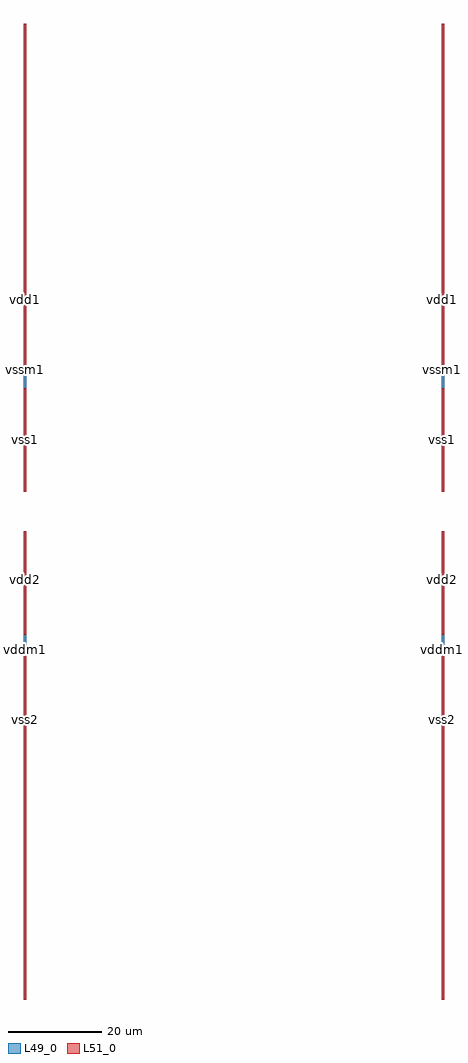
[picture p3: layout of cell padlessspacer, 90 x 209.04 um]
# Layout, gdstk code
import gdstk
lib = gdstk.Library(unit=1e-6, precision=1e-08)
def R(c, l, rs):  # rectangles x0, y0, x1, y1
    for r in rs: c.add(gdstk.rectangle(r[:2], r[2:], *l))
L49_0 = (49, 0)
L51_0 = (51, 0)

padlessspacer = lib.new_cell('padlessspacer')
R(padlessspacer, L49_0, [(0,0,0.48,100.32), (89.52,0,90,100.32), (0,108.72,0.48,209.04), (89.52,108.72,90,209.04)])
R(padlessspacer, L51_0, [(0,0,0.48,73.92), (89.52,0,90,73.92), (0,78.12,0.48,100.32), (89.52,78.12,90,100.32), (0,108.72,0.48,130.92), (89.52,108.72,90,130.92), (0,135.12,0.48,209.04), (89.52,135.12,90,209.04)])
padlessspacer.add(gdstk.Label('vdd1', (89.76,150), layer=125, texttype=0))
padlessspacer.add(gdstk.Label('vdd1', (0.24,150), layer=125, texttype=0))
padlessspacer.add(gdstk.Label('vdd2', (89.76,90), layer=125, texttype=0))
padlessspacer.add(gdstk.Label('vdd2', (0.24,90), layer=125, texttype=0))
padlessspacer.add(gdstk.Label('vss2', (89.76,60), layer=125, texttype=0))
padlessspacer.add(gdstk.Label('vss2', (0.24,60), layer=125, texttype=0))
padlessspacer.add(gdstk.Label('vss1', (89.76,120), layer=125, texttype=0))
padlessspacer.add(gdstk.Label('vss1', (0.24,120), layer=125, texttype=0))
padlessspacer.add(gdstk.Label('vssm1', (89.76,135), layer=126, texttype=0))
padlessspacer.add(gdstk.Label('vssm1', (0.24,135), layer=126, texttype=0))
padlessspacer.add(gdstk.Label('vddm1', (89.76,75), layer=126, texttype=0))
padlessspacer.add(gdstk.Label('vddm1', (0.24,75), layer=126, texttype=0))

lib.write_gds('padlessspacer.gds')
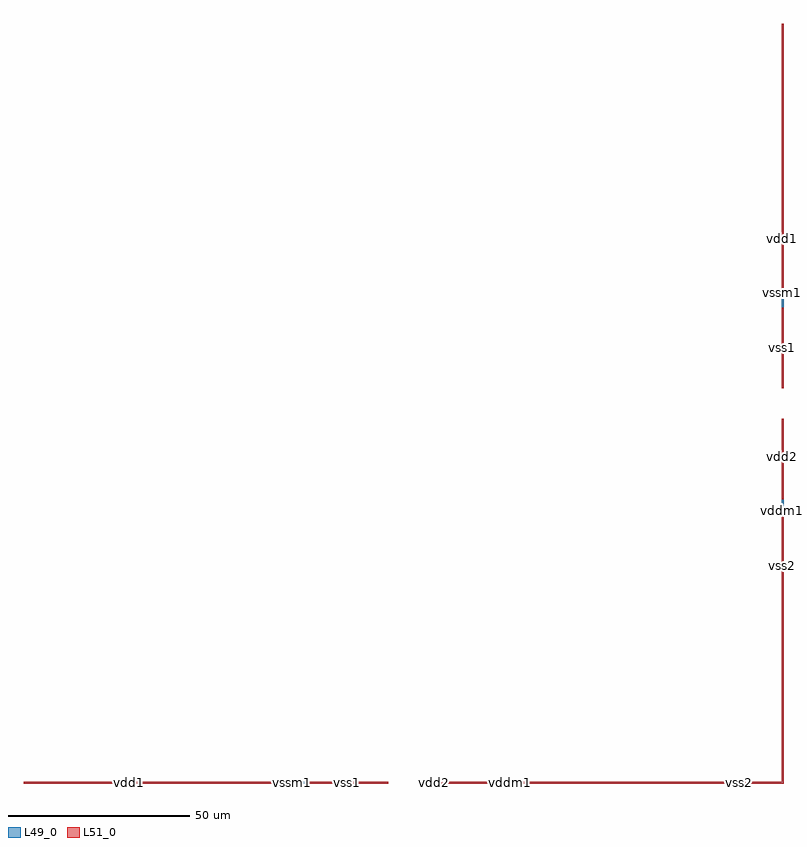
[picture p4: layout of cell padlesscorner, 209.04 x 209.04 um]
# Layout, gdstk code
import gdstk
lib = gdstk.Library(unit=1e-6, precision=1e-08)
def R(c, l, rs):  # rectangles x0, y0, x1, y1
    for r in rs: c.add(gdstk.rectangle(r[:2], r[2:], *l))
L49_0 = (49, 0)
L51_0 = (51, 0)

padlesscorner = lib.new_cell('padlesscorner')
R(padlesscorner, L49_0, [(90.96,0,191.28,0.48), (199.68,0,300,0.48), (299.52,0,300,100.32), (299.52,108.72,300,209.04)])
R(padlesscorner, L51_0, [(90.96,0,164.88,0.48), (169.08,0,191.28,0.48), (199.68,0,221.88,0.48), (226.08,0,300,0.48), (299.52,0,300,73.92), (299.52,78.12,300,100.32), (299.52,108.72,300,130.92), (299.52,135.12,300,209.04)])
padlesscorner.add(gdstk.Label('vdd1', (299.76,150), layer=125, texttype=0))
padlesscorner.add(gdstk.Label('vdd1', (120,0.24), layer=125, texttype=0))
padlesscorner.add(gdstk.Label('vdd2', (299.76,90), layer=125, texttype=0))
padlesscorner.add(gdstk.Label('vdd2', (204,0.24), layer=125, texttype=0))
padlesscorner.add(gdstk.Label('vss2', (299.76,60), layer=125, texttype=0))
padlesscorner.add(gdstk.Label('vss2', (288,0.24), layer=125, texttype=0))
padlesscorner.add(gdstk.Label('vss1', (299.76,120), layer=125, texttype=0))
padlesscorner.add(gdstk.Label('vss1', (180,0.24), layer=125, texttype=0))
padlesscorner.add(gdstk.Label('vssm1', (299.76,135), layer=126, texttype=0))
padlesscorner.add(gdstk.Label('vssm1', (165,0.24), layer=126, texttype=0))
padlesscorner.add(gdstk.Label('vddm1', (299.76,75), layer=126, texttype=0))
padlesscorner.add(gdstk.Label('vddm1', (225,0.24), layer=126, texttype=0))

lib.write_gds('padlesscorner.gds')
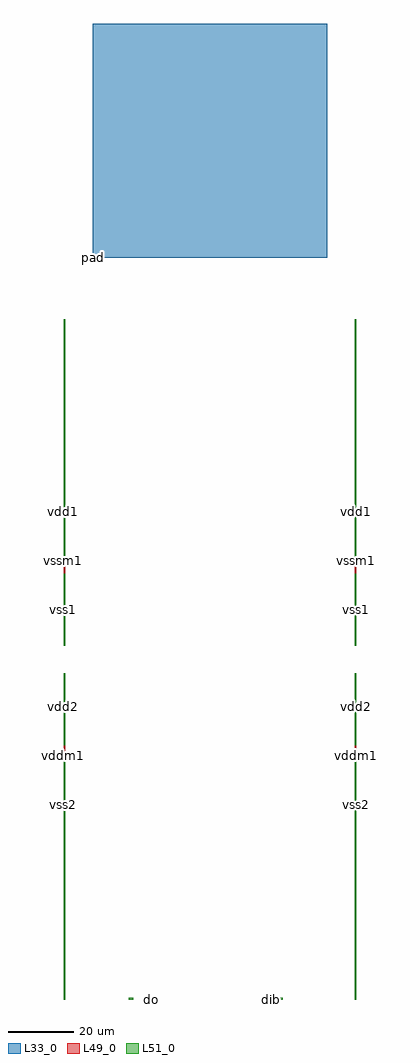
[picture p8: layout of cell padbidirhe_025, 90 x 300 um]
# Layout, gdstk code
import gdstk
lib = gdstk.Library(unit=1e-6, precision=1e-08)
def R(c, l, rs):  # rectangles x0, y0, x1, y1
    for r in rs: c.add(gdstk.rectangle(r[:2], r[2:], *l))
L33_0 = (33, 0)
L49_0 = (49, 0)
L51_0 = (51, 0)

padbidirhe_025 = lib.new_cell('padbidirhe_025')
R(padbidirhe_025, L33_0, [(9,228,81,300)])
R(padbidirhe_025, L49_0, [(0,0,0.48,100.32), (89.52,0,90,100.32), (0,108.72,0.48,209.04), (89.52,108.72,90,209.04)])
R(padbidirhe_025, L51_0, [(0,0,0.48,73.92), (19.98,0,21.36,0.48), (26.28,0,27.6,0.48), (63.36,0,64.68,0.48), (66,0,67.32,0.48), (89.52,0,90,73.92), (0,78.12,0.48,100.32), (89.52,78.12,90,100.32), (0,108.72,0.48,130.92), (89.52,108.72,90,130.92), (0,135.12,0.48,209.04), (89.52,135.12,90,209.04)])
padbidirhe_025.add(gdstk.Label('vddm1', (0.12,75), layer=126, texttype=0))
padbidirhe_025.add(gdstk.Label('vddm1', (89.88,75), layer=126, texttype=0))
padbidirhe_025.add(gdstk.Label('vssm1', (0.12,135), layer=126, texttype=0))
padbidirhe_025.add(gdstk.Label('vssm1', (89.88,135), layer=126, texttype=0))
padbidirhe_025.add(gdstk.Label('vss1', (0.12,120), layer=125, texttype=0))
padbidirhe_025.add(gdstk.Label('vss1', (89.88,120), layer=125, texttype=0))
padbidirhe_025.add(gdstk.Label('vss2', (0.12,60), layer=125, texttype=0))
padbidirhe_025.add(gdstk.Label('vss2', (89.88,60), layer=125, texttype=0))
padbidirhe_025.add(gdstk.Label('vdd2', (0.12,90), layer=125, texttype=0))
padbidirhe_025.add(gdstk.Label('vdd2', (89.88,90), layer=125, texttype=0))
padbidirhe_025.add(gdstk.Label('vdd1', (0.12,150), layer=125, texttype=0))
padbidirhe_025.add(gdstk.Label('vdd1', (89.88,150), layer=125, texttype=0))
padbidirhe_025.add(gdstk.Label('dib', (64.02,0.12), layer=125, texttype=0))
padbidirhe_025.add(gdstk.Label('di', (66.72,0.12), layer=125, texttype=0))
padbidirhe_025.add(gdstk.Label('do', (26.94,0.12), layer=125, texttype=0))
padbidirhe_025.add(gdstk.Label('oeb', (20.7,0.12), layer=125, texttype=0))
padbidirhe_025.add(gdstk.Label('pad', (9.12,228.12), layer=124, texttype=0))

lib.write_gds('padbidirhe_025.gds')
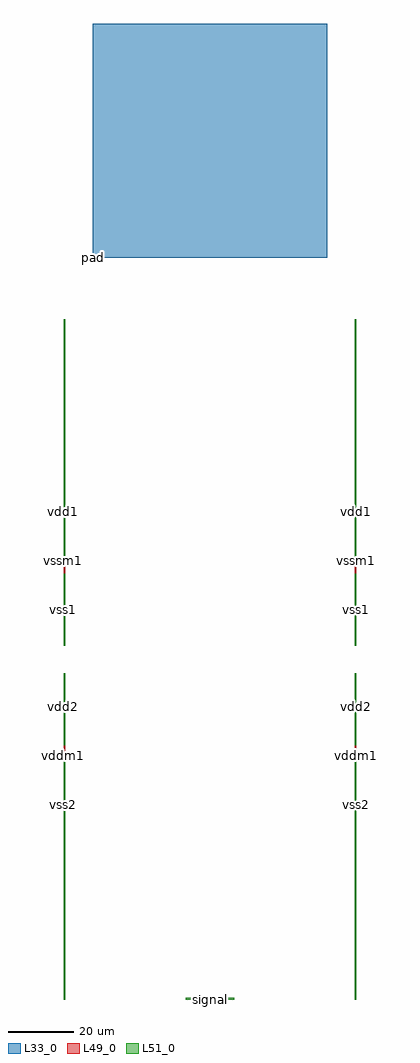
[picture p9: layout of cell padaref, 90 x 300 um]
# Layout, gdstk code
import gdstk
lib = gdstk.Library(unit=1e-6, precision=1e-08)
def R(c, l, rs):  # rectangles x0, y0, x1, y1
    for r in rs: c.add(gdstk.rectangle(r[:2], r[2:], *l))
L33_0 = (33, 0)
L49_0 = (49, 0)
L51_0 = (51, 0)

padaref = lib.new_cell('padaref')
R(padaref, L33_0, [(9,228,81,300)])
R(padaref, L49_0, [(0,0,0.48,100.32), (89.52,0,90,100.32), (0,108.72,0.48,209.04), (89.52,108.72,90,209.04)])
R(padaref, L51_0, [(0,0,0.48,73.92), (37.56,0,52.44,0.48), (89.52,0,90,73.92), (0,78.12,0.48,100.32), (89.52,78.12,90,100.32), (0,108.72,0.48,130.92), (89.52,108.72,90,130.92), (0,135.12,0.48,209.04), (89.52,135.12,90,209.04)])
padaref.add(gdstk.Label('vddm1', (0.12,75), layer=126, texttype=0))
padaref.add(gdstk.Label('vddm1', (89.88,75), layer=126, texttype=0))
padaref.add(gdstk.Label('vssm1', (0.12,135), layer=126, texttype=0))
padaref.add(gdstk.Label('vssm1', (89.88,135), layer=126, texttype=0))
padaref.add(gdstk.Label('vss1', (0.12,120), layer=125, texttype=0))
padaref.add(gdstk.Label('vss1', (89.88,120), layer=125, texttype=0))
padaref.add(gdstk.Label('vss2', (0.12,60), layer=125, texttype=0))
padaref.add(gdstk.Label('vss2', (89.88,60), layer=125, texttype=0))
padaref.add(gdstk.Label('vdd2', (0.12,90), layer=125, texttype=0))
padaref.add(gdstk.Label('vdd2', (89.88,90), layer=125, texttype=0))
padaref.add(gdstk.Label('vdd1', (0.12,150), layer=125, texttype=0))
padaref.add(gdstk.Label('vdd1', (89.88,150), layer=125, texttype=0))
padaref.add(gdstk.Label('signal', (45,0.12), layer=125, texttype=0))
padaref.add(gdstk.Label('pad', (9.12,228.12), layer=124, texttype=0))

lib.write_gds('padaref.gds')
